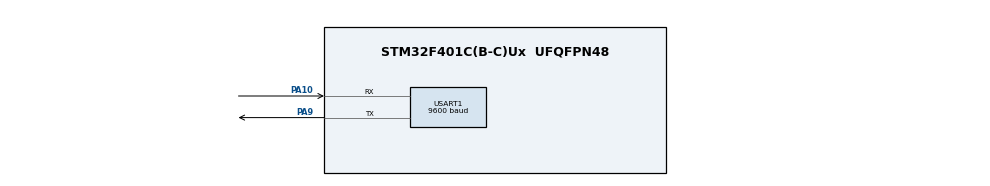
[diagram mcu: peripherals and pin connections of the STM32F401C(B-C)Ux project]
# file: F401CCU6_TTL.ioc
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Mcu.Family=STM32F4
Mcu.Name=STM32F401C(B-C)Ux
Mcu.Package=UFQFPN48
NVIC.PriorityGroup=NVIC_PRIORITYGROUP_4
NVIC.USART1_IRQn=true\:0\:0\:false\:false\:true\:true\:true\:true
PA10.Mode=Asynchronous
PA10.Signal=USART1_RX
PA13.Mode=Serial_Wire
PA13.Signal=SYS_JTMS-SWDIO
PA14.Mode=Serial_Wire
PA14.Signal=SYS_JTCK-SWCLK
PA9.Mode=Asynchronous
PA9.Signal=USART1_TX
PC14-OSC32_IN.Mode=LSE-External-Oscillator
PC14-OSC32_IN.Signal=RCC_OSC32_IN
PC15-OSC32_OUT.Mode=LSE-External-Oscillator
PC15-OSC32_OUT.Signal=RCC_OSC32_OUT
PH0\ -\ OSC_IN.Mode=HSE-External-Oscillator
PH0\ -\ OSC_IN.Signal=RCC_OSC_IN
PH1\ -\ OSC_OUT.Mode=HSE-External-Oscillator
PH1\ -\ OSC_OUT.Signal=RCC_OSC_OUT
ProjectManager.HeapSize=0x200
ProjectManager.StackSize=0x400
ProjectManager.TargetToolchain=STM32CubeIDE
RCC.48MHZClocksFreq_Value=42000000
RCC.AHBFreq_Value=16000000
RCC.APB1CLKDivider=RCC_HCLK_DIV2
RCC.APB1Freq_Value=8000000
RCC.APB1TimFreq_Value=16000000
RCC.APB2Freq_Value=16000000
RCC.APB2TimFreq_Value=16000000
RCC.CortexFreq_Value=16000000
RCC.HCLKFreq_Value=16000000
RCC.HSE_VALUE=25000000
RCC.HSI_VALUE=16000000
RCC.PLLM=8
RCC.PLLN=84
RCC.SYSCLKFreq_VALUE=16000000
RCC.VCOOutputFreq_Value=168000000
USART1.BaudRate=9600
USART1.VirtualMode=VM_ASYNC
board=custom

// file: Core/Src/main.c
/* USER CODE BEGIN Header */
/**
 ******************************************************************************
 * @file           : main.c
 * @brief          : Main program body
 ******************************************************************************
 * @attention
 *
 * Copyright (c) 2025 STMicroelectronics.
 * All rights reserved.
 *
 * This software is licensed under terms that can be found in the LICENSE file
 * in the root directory of this software component.
 * If no LICENSE file comes with this software, it is provided AS-IS.
 *
 ******************************************************************************
 */
/* USER CODE END Header */
#include "main.h"
#include<string.h>

UART_HandleTypeDef huart1;

/* USER CODE BEGIN PV */
uint8_t rx_data;
/* USER CODE END PV */

void SystemClock_Config(void);
static void MX_GPIO_Init(void);
static void MX_USART1_UART_Init(void);

int main(void) {

	/* MCU Configuration--------------------------------------------------------*/

	/* Reset of all peripherals, Initializes the Flash interface and the Systick. */
	HAL_Init();

	/* Configure the system clock */
	SystemClock_Config();

	/* Initialize all configured peripherals */
	MX_GPIO_Init();
	MX_USART1_UART_Init();
	/* USER CODE BEGIN 2 */
	HAL_UART_Transmit(&huart1, (uint8_t*) "Ready\r\n", 7, HAL_MAX_DELAY);
	HAL_UART_Receive_IT(&huart1, &rx_data, 1);
	/* USER CODE END 2 */

	/* Infinite loop */
	while (1) {

	}
}

void HAL_UART_RxCpltCallback(UART_HandleTypeDef *huart) {
	if (huart->Instance == USART1) {
		HAL_UART_Transmit(&huart1, &rx_data, 1, HAL_MAX_DELAY);  // Echo
		HAL_UART_Receive_IT(&huart1, &rx_data, 1);               // Restart
	}

}

void SystemClock_Config(void) {
	RCC_OscInitTypeDef RCC_OscInitStruct = { 0 };
	RCC_ClkInitTypeDef RCC_ClkInitStruct = { 0 };

	/** Configure the main internal regulator output voltage */
	__HAL_RCC_PWR_CLK_ENABLE();
	__HAL_PWR_VOLTAGESCALING_CONFIG(PWR_REGULATOR_VOLTAGE_SCALE2);

	/** Initializes the RCC Oscillators (HSE -> PLL -> SYSCLK 84 MHz) */
	RCC_OscInitStruct.OscillatorType = RCC_OSCILLATORTYPE_HSI;
	RCC_OscInitStruct.HSIState = RCC_HSI_ON;
	RCC_OscInitStruct.HSICalibrationValue = RCC_HSICALIBRATION_DEFAULT;

	RCC_OscInitStruct.PLL.PLLState = RCC_PLL_ON;
	RCC_OscInitStruct.PLL.PLLSource = RCC_PLLSOURCE_HSI;
	RCC_OscInitStruct.PLL.PLLM = 16;
	RCC_OscInitStruct.PLL.PLLN = 336;
	RCC_OscInitStruct.PLL.PLLP = RCC_PLLP_DIV4;   // 336 / 4 = 84 MHz
	RCC_OscInitStruct.PLL.PLLQ = 7;

	if (HAL_RCC_OscConfig(&RCC_OscInitStruct) != HAL_OK)
		Error_Handler();

	/** Initializes the CPU, AHB and APB buses clocks */
	RCC_ClkInitStruct.ClockType = RCC_CLOCKTYPE_HCLK | RCC_CLOCKTYPE_SYSCLK
			| RCC_CLOCKTYPE_PCLK1 | RCC_CLOCKTYPE_PCLK2;

	RCC_ClkInitStruct.SYSCLKSource = RCC_SYSCLKSOURCE_PLLCLK;  // PLL as source
	RCC_ClkInitStruct.AHBCLKDivider = RCC_SYSCLK_DIV1;
	RCC_ClkInitStruct.APB1CLKDivider = RCC_HCLK_DIV2;  // APB1 = 42 MHz
	RCC_ClkInitStruct.APB2CLKDivider = RCC_HCLK_DIV1;  // APB2 = 84 MHz

	if (HAL_RCC_ClockConfig(&RCC_ClkInitStruct, FLASH_LATENCY_2) != HAL_OK)
		Error_Handler();
}

static void MX_USART1_UART_Init(void) {

	huart1.Instance = USART1;
	huart1.Init.BaudRate = 9600;
	huart1.Init.WordLength = UART_WORDLENGTH_8B;
	huart1.Init.StopBits = UART_STOPBITS_1;
	huart1.Init.Parity = UART_PARITY_NONE;
	huart1.Init.Mode = UART_MODE_TX_RX;
	huart1.Init.HwFlowCtl = UART_HWCONTROL_NONE;
	huart1.Init.OverSampling = UART_OVERSAMPLING_16;
	if (HAL_UART_Init(&huart1) != HAL_OK) {
		Error_Handler();
	}

}

static void MX_GPIO_Init(void) {

	/* GPIO Ports Clock Enable */
	__HAL_RCC_GPIOC_CLK_ENABLE();
	__HAL_RCC_GPIOH_CLK_ENABLE();
	__HAL_RCC_GPIOA_CLK_ENABLE();

}

void Error_Handler(void) {
	__disable_irq();
	while (1) {
	}
}
